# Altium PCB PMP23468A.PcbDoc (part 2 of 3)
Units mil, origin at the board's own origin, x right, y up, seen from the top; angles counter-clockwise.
Board outline 5250 x 3500 mil, 6 copper layers (Top Layer, Signal Layer 1, Signal Layer 2, Signal Layer 3, Signal Layer 4, Bottom Layer), stack 61.8 mil thick; 157 components, 73 nets, 403 pads, 842 vias.

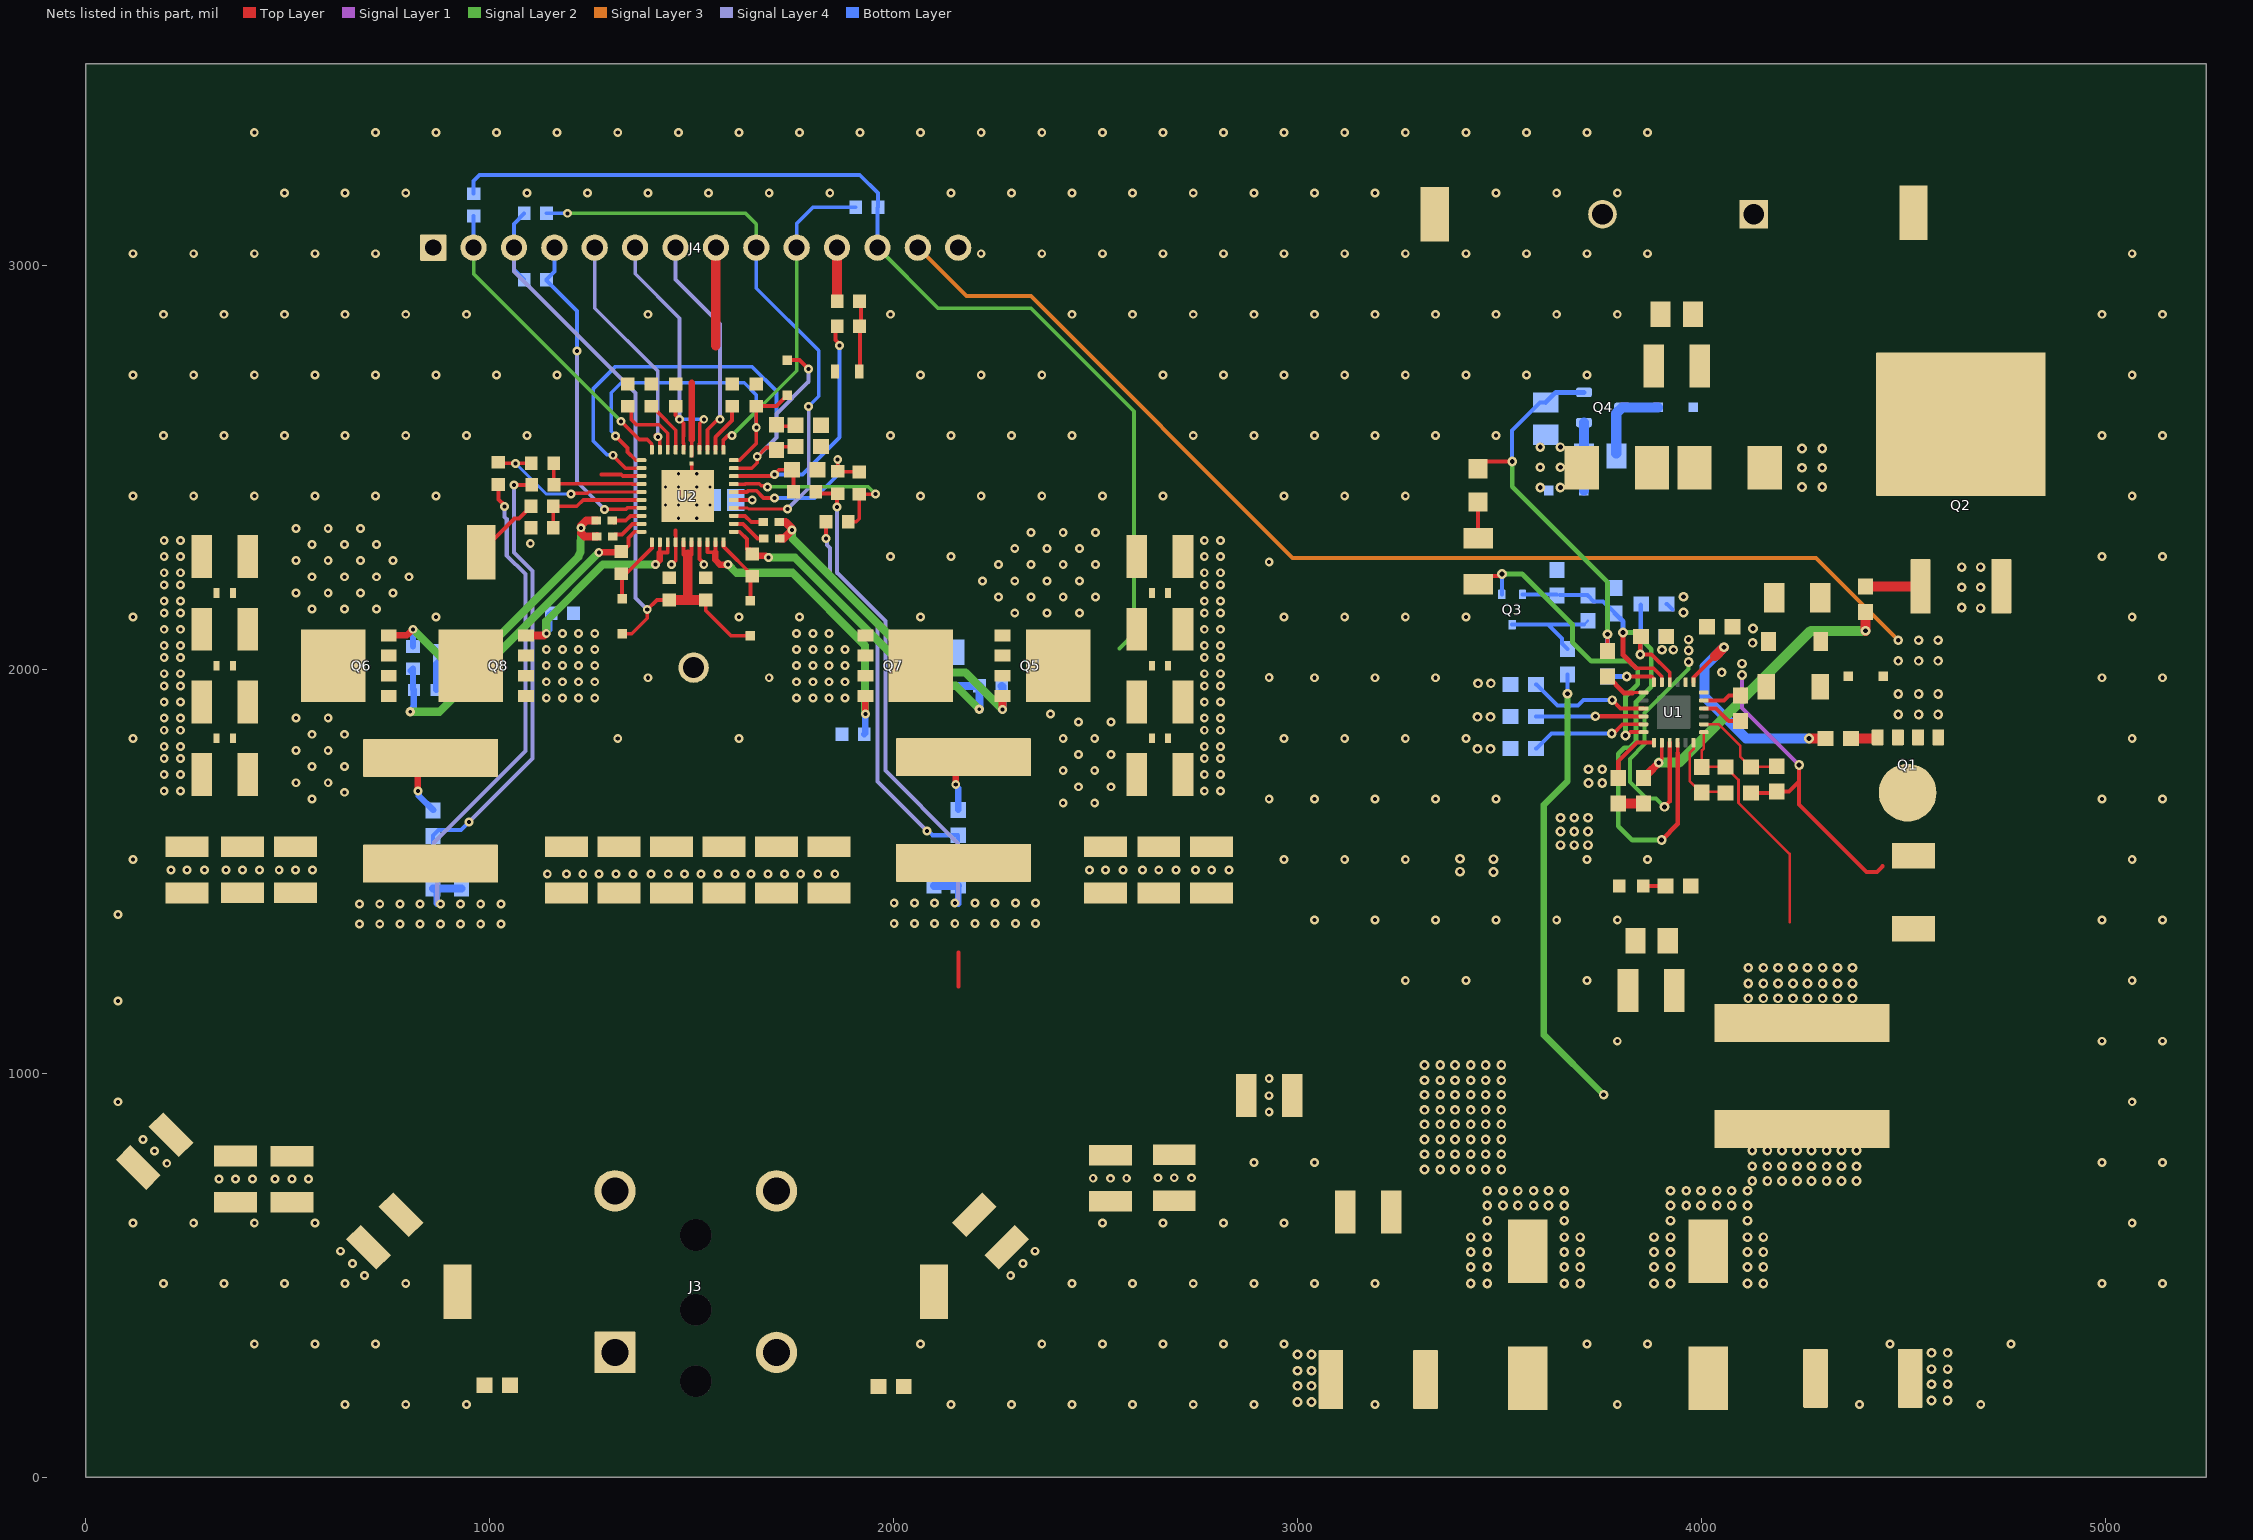
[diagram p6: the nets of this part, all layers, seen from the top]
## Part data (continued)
R9: library part CMP-0022456-4, "RES, 4.75 k, 1%, 0.1 W, AEC-Q200 Grade 0, 0603", Manufacturer=Vishay-Dale, Power_W=100mW, Supplier Part Number 1=541-4.75KHCT-ND, TempCo="100 ppm/C", Tolerance_%=1%, Value2=0.1W, Value_Code=4k75, ValueDisplayed=4.75k
R10 R16: library part CMP-0018576-3, "RES, 10 k, 5%, 0.25 W, AEC-Q200 Grade 0, 1206", Manufacturer=Vishay-Dale, Power_W=250mW, Supplier Part Number 1=541-10KECT-ND, TempCo="200 ppm/C", Tolerance_%=5%, Value2=0.25W, Value_Code=10k0, ValueDisplayed=10k
R11: library part CMP-0022134-4, "RES, 1.82 k, 1%, 0.1 W, AEC-Q200 Grade 0, 0603", Manufacturer=Vishay-Dale, PartNumber=CRCW06031K82FKEA, Power_W=100mW, Supplier Part Number 1=541-1.82KHCT-ND, TempCo="100 ppm/C", Tolerance_%=1%, Value2=0.1W, Value_Code=1k82, ValueDisplayed=1.82k
R12: library part CMP-0022479-4, "RES, 50, 1%, 0.1 W, AEC-Q200 Grade 0, 0603", Manufacturer=Vishay-Dale, Power_W=100mW, Supplier Part Number 1=89M6778, TempCo="100 ppm/C", Tolerance_%=1%, Value2=0.1W, Value_Code=50R0, ValueDisplayed=50
R14: library part CMP-0022132-4, "RES, 1.74 k, 1%, 0.1 W, AEC-Q200 Grade 0, 0603", Manufacturer=Vishay-Dale, Power_W=100mW, Supplier Part Number 1=541-1.74KHCT-ND, TempCo="100 ppm/C", Tolerance_%=1%, Value2=0.1W, Value_Code=1k74, ValueDisplayed=1.74k
R15 R19 R33 R34: library part CMP-0023341-3, "RES, 10.0 k, 1%, 0.1 W, AEC-Q200 Grade 0, 0603", Manufacturer="Stackpole Electronics Inc", Power_W=100mW, Supplier Part Number 1=RMCF0603FT10K0CT-ND, TempCo="100 ppm/C", Tolerance_%=1%, Value2=0.1W, Value_Code=10k0, ValueDisplayed=10.0k
R17: library part CMP-0022112-4, "RES, 1.07 k, 1%, 0.1 W, AEC-Q200 Grade 0, 0603", Manufacturer=Vishay-Dale, PartNumber=CRCW06031K07FKEA, Power_W=100mW, Supplier Part Number 1=541-1.07KHCT-ND, TempCo="100 ppm/C", Tolerance_%=1%, Value2=0.1W, Value_Code=1k07, ValueDisplayed=1.07k
R18: library part CMP-0025700-4, "RES, 100, 5%, 0.1 W, AEC-Q200 Grade 0, 0603", Manufacturer=Vishay-Dale, Power_W=100mW, Supplier Part Number 1=541-100GCT-ND, TempCo="200 ppm/C", Tolerance_%=5%, Value2=0.1W, Value_Code=100R, ValueDisplayed=100
R20: library part CMP-0022377-4, "RES, 3.48 k, 1%, 0.1 W, AEC-Q200 Grade 0, 0603", Manufacturer=Vishay-Dale, PartNumber=CRCW06033K48FKEA, Power_W=100mW, Supplier Part Number 1=541-3.48KHCT-ND, TempCo="100 ppm/C", Tolerance_%=1%, Value2=0.1W, Value_Code=3k48, ValueDisplayed=3.48k
R21: library part CMP-0022067-4, "RES, 15.4 k, 1%, 0.1 W, AEC-Q200 Grade 0, 0603", Manufacturer=Vishay-Dale, PartNumber=CRCW060315K4FKEA, Power_W=100mW, Supplier Part Number 1=541-15.4KHCT-ND, TempCo="100 ppm/C", Tolerance_%=1%, Value2=0.1W, Value_Code=15k4, ValueDisplayed=15.4k
R22: library part CMP-0022900-4, "RES, 1.00, 1%, 0.1 W, 0603", Manufacturer=Yageo, Power_W=100mW, Supplier Part Number 1=311-1.00HRCT-ND, TempCo="200 ppm/C", Tolerance_%=1%, Value2=0.1W, Value_Code=1R00, ValueDisplayed=1.00
R23 R24 R26 R27: library part CMP-0026992-3, "RES, 0, 5%, 0.1 W, AEC-Q200 Grade 0, 0402", Manufacturer=Panasonic, Power_W=100mW, Supplier Part Number 1=P0.0JCT-ND, TempCo="600 ppm/C", Tolerance_%=5%, Value2=0.1W, Value_Code=0000, ValueDisplayed=0
R29 R30: library part CMP-0022000-4, "RES, 10.5 k, 1%, 0.1 W, AEC-Q200 Grade 0, 0603", Manufacturer=Vishay-Dale, Power_W=100mW, Supplier Part Number 1=541-10.5KHCT-ND, TempCo="100 ppm/C", Tolerance_%=1%, Value2=0.1W, Value_Code=10k5, ValueDisplayed=10.5k
R31 R32: library part CMP-0020693-3, "RES, 2.2, 5%, 0.125 W, AEC-Q200 Grade 0, 0805", Manufacturer=Panasonic, Power_W=125mW, Supplier Part Number 1=P2.2ACT-ND, TempCo="600 ppm/C", Tolerance_%=5%, Value2=0.125W, Value_Code=2R20, ValueDisplayed=2.2
R37 R40 R51: library part CMP-0025697-4, "RES, 0, 5%, 0.1 W, AEC-Q200 Grade 0, 0603", Manufacturer=Vishay-Dale, Power_W=100mW, Supplier Part Number 1=541-0.0GCT-ND, TempCo="200 ppm/C", Tolerance_%=5%, Value2=0.1W, Value_Code=0000, ValueDisplayed=0
R38 R39: library part CMP-0021991-4, "RES, 100, 1%, 0.1 W, AEC-Q200 Grade 0, 0603", Manufacturer=Vishay-Dale, Power_W=100mW, Supplier Part Number 1=541-100HCT-ND, TempCo="100 ppm/C", Tolerance_%=1%, Value2=0.1W, Value_Code=100R, ValueDisplayed=100
R41: library part CMP-0022441-4, "RES, 487 k, 1%, 0.1 W, AEC-Q200 Grade 0, 0603", Manufacturer=Vishay-Dale, PartNumber=CRCW0603487KFKEA, Power_W=100mW, Supplier Part Number 1=541-487KHCT-ND, TempCo="100 ppm/C", Tolerance_%=1%, Value2=0.1W, Value_Code=487k
R42: library part CMP-0022111-4, "RES, 1.05 k, 1%, 0.1 W, AEC-Q200 Grade 0, 0603", Manufacturer=Vishay-Dale, Power_W=100mW, Supplier Part Number 1=541-1.05KHCT-ND, TempCo="100 ppm/C", Tolerance_%=1%, Value2=0.1W, Value_Code=1k05, ValueDisplayed=1.05k
R43: library part CMP-0022452-4, "RES, 4.32 k, 1%, 0.1 W, AEC-Q200 Grade 0, 0603", Manufacturer=Vishay-Dale, Power_W=100mW, Supplier Part Number 1=541-4.32KHCT-ND, TempCo="100 ppm/C", Tolerance_%=1%, Value2=0.1W, Value_Code=4k32, ValueDisplayed=4.32k
R48: library part CMP-0022494-4, "RES, 54.9 k, 1%, 0.1 W, AEC-Q200 Grade 0, 0603", Manufacturer=Vishay-Dale, Power_W=100mW, Supplier Part Number 1=541-54.9KHCT-ND, TempCo="100 ppm/C", Tolerance_%=1%, Value2=0.1W, Value_Code=54k9, ValueDisplayed=54.9k
R49: library part CMP-0022018-4, "RES, 11.5 k, 1%, 0.1 W, AEC-Q200 Grade 0, 0603", Manufacturer=Vishay-Dale, Power_W=100mW, Supplier Part Number 1=541-11.5KHCT-ND, TempCo="100 ppm/C", Tolerance_%=1%, Value2=0.1W, Value_Code=11k5, ValueDisplayed=11.5k
R50: library part CMP-0025686-1, "RES, 10.0 k, 0.1%, 0.1 W, AEC-Q200 Grade 1, 0603", Manufacturer=Vishay-Dale, PartNumber=TNPW060310K0BEEA, Power_W=100mW, Supplier Part Number 1=TNP10.0KAACT-ND, TempCo="25 ppm/C", Tolerance_%=0.1%, Value2=0.1W, Value_Code=10k0, ValueDisplayed=10.0k
SH-J1: library part CMP-0078738-1, "Single Operation 2.54mm Pitch Open Top Jumper Socket", Manufacturer=Harwin, Supplier Part Number 1=952-2881-ND
TP1 TP2 TP3 TP4 TP5: library part CMP-0055152-2, "Test Point, Miniature, SMT", Manufacturer="Keystone Electronics", Supplier Part Number 1=36-5015TR-ND
U1: library part CMP-0021701-1, "Ideal Diode Surge Stopper with Circuit breaker, overvoltage protection and fault output", Manufacturer="Texas Instruments", Max Supply Voltage=65V, Min Supply Voltage=3V, Nominal Supply Current=650-700uA, Operating Temperature Range="-40°C to +150°C"
U2: library part CMP-0094639-1, "Automotive 3.5-V to 65-V Dual Synchronous Buck Controller With Low IQ", Manufacturer="Texas Instruments", Max Supply Voltage=65V, Min Supply Voltage=3.5V, Nominal Supply Current=15-25uA, Operating Temperature Range="-40°C to +150°C", Output Voltage=0.6-55V, Switching Frequency=0.1-2.2MHz

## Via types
v1: diameter 22, hole 10, Top Layer to Bottom Layer, tented both sides, 567 vias
v2: diameter 24, hole 12, Top Layer to Bottom Layer, tented both sides, 172 vias
v3: diameter 24, hole 12, Top Layer to Bottom Layer, 84 vias
v4: diameter 19.68, hole 7.87, Top Layer to Bottom Layer, 12 vias
v5: diameter 19.68, hole 7.87, Top Layer to Bottom Layer, tented both sides, 5 vias
v6: diameter 24, hole 8, Top Layer to Bottom Layer, tented both sides, 2 vias

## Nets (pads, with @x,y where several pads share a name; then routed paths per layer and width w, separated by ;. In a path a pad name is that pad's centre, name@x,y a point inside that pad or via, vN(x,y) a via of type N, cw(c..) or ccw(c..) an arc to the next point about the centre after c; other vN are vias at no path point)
A: C1.1 D5.2 J4.13 Q1.1 Q1.2 Q1.3 Q2.3 U1.2 U1.15 | length 3462.7
  Top Layer w10: v3(3909.01,1660.24) 3921.86,1673.1 U1.15@3921.86,1819.51
  Signal Layer 2 w10: v3(3909.01,1660.24) 3887.93,1681.32 3864.71,1681.32 3823.71,1722.32 3823.71,1779.32 3859.91,1815.52 3859.91,1892.52 3968.61,2001.22 v3(3968.61,2018.87)
  Signal Layer 3 w10: J4.13@2060,3045 2180,2925 2340,2925 2988.01,2276.99 4283.64,2276.99 v3(4487.81,2072.82)
  other v3: 4487.81,1888.82 4538.11,1888.82 4586.41,1888.82 4487.81,1939.82 4538.11,1939.82 4586.41,1939.82 4487.81,2021.82 4538.11,2021.82 4586.41,2021.82 3968.61,2047.22 4538.11,2072.82 4586.41,2072.82 3968.61,2074.32 4691.71,2152.32 4644.91,2153.92 4644.91,2203.92 4691.71,2203.92 4644.91,2253.92 4691.71,2253.92
AGND: C18.1 C66.1 C67.2 C68.2 C69.2 C70.2 J4.8 NT1.1 R48.1 R50.1 R51.2 U2.3 U2.35 | length 523.6
  Top Layer w9: NT1.1@1499.84,2530 U2.35@1499.84,2544.17 1499.84,2569.84
  Top Layer w9.5: 1276.38,2483.62 1324.79,2483.62 1329.2,2479.21 U2.3@1375.83,2479.21
  Top Layer w16: 1499.84,2569.84 1500,2570 1500,2710
  Top Layer w24: 1560,2802.78 J4.8@1560,3045
COMP: C69.1 D11.2 R49.2 U2.2 U2.29 | length 1486.8
  Top Layer w9: v1@1310,2530 1309.07,2530.93 v1(1305,2530.93) 1305,2530 1336.1,2498.9 U2.2@1375.83,2498.9 ; U2.29@1604.17,2498.9 1648.9,2498.9 1662.44,2512.44 v1(1662.44,2527.44) 1685,2550 1707.44,2550 1710,2547.44 1714.75,2552.19 C69.1@1761.33,2552.19
  Top Layer w10: D11.2@1737.15,2766.33 1767.49,2766.33 v1(1789.59,2744.23)
  Signal Layer 4 w10: v1(1662.44,2527.44) 1710,2575 1710,2633.35 1789.59,2712.94 v1(1789.59,2744.23)
  Bottom Layer w9: v1(1305,2530.93) 1303.4,2532.53 1289.95,2532.53 1256.7,2565.78 1256.7,2696.2 1310.16,2749.67 1611.14,2749.99 ; 1611.14,2749.69 1650.32,2749.69 1710,2690 1710,2575 v1(1662.44,2527.44)
DEMB: J4.7 U2.33 | length 550
  Top Layer w9: U2.33@1539.21,2544.17 1539.21,2594.21 1560,2615
  Signal Layer 4 w9: J4.7@1460,3045 1460,2965.98 1570,2855.98 v1(1570,2620)
EN1: J4.10 R47.1 U2.31 | length 804.4
  Top Layer w9: U2.31@1578.58,2544.17 1578.58,2568.58 1590,2580 v1(1600,2580)
  Signal Layer 2 w9: v1(1600,2580) 1760,2740 J4.10@1760,3045
  Bottom Layer w9: J4.10@1760,3045 1760,3104.76 1800.24,3145 R47.1@1906.18,3145
EN2: J4.2 R46.1 U2.40 | length 773.5
  Top Layer w9: v1(1325,2615) 1370,2570 1390,2570 1401.42,2558.58 U2.40@1401.42,2544.17
  Signal Layer 2 w9: J4.2@960,3045 960,2980 v1(1325,2615)
  Bottom Layer w10: J4.2@960,3045 R46.1@960,3123.11
FB1: R41.1 R43.1 R50.2 U2.28 | length 688.3
  Top Layer w9.5: U2.28@1604.17,2479.21 1700.79,2479.21 v1(1705,2483.43) 1716.57,2495 R50.2@1748.5,2495 1752.44,2495 R41.1@1752.44,2440
  Top Layer w10: R43.1@1856.57,2850.31 1856.57,2815.87 1866.41,2806.03 v1(1866.41,2802.78)
  Bottom Layer w10: v1(1705,2483.43) 1774.36,2483.43 1866.41,2575.47 v1(1866.41,2802.78)
FLT/: Q3.1 R16.1 U1.12 | length 804.3
  Top Layer w10: R16.1@3447.56,2211.27 3468.15,2231.86 3498.86,2231.86 3503.86,2236.86 v3(3506.57,2236.86) ; v3(3812.32,1836.8) 3816.11,1836.8 3824.41,1845.11 U1.12@3856.9,1845.11
  Signal Layer 2 w12: v3(3506.57,2236.86) 3556.16,2236.86 3680.71,2112.32 3680.71,2068.32 3727.71,2021.32 3820.81,2021.32 3842.71,1999.42 3842.71,1964.32 3812.32,1933.93 v3(3812.32,1836.8)
  Bottom Layer w6: Q3.1@3506.12,2186.17 Q3.1@3506.34,2186.4 ; v3@3506.34,2236.64 v3(3506.57,2236.86)
  Bottom Layer w10: Q3.1@3506.34,2186.4 v3@3506.34,2236.64 ; v3(3506.57,2236.86) v3@3506.76,2237.06
NetC2_2: C2.2 R6.2
NetC3_2: C3.2 R7.2
NetC6_1: C6.1 C7.1 C12.2 C13.2 L1.1 R1.2 R2.1 U1.19 | length 597.6
  Top Layer w6.5: U1.19@4006.51,1845.11 4006.51,1805.12 4001.21,1799.82 C12.2@4001.21,1759.31 C13.2@4060.21,1759.32 4092.21,1727.32 4092.21,1670.12 4218.71,1543.62 4218.71,1374.32
  other v2: 4116.23,1186.13 4153.63,1186.13 4189.7,1186.13 4227.11,1186.13 4263.03,1186.13 4300.44,1186.13 4337.17,1186.13 4374.58,1186.13 4116.23,1222.75 4153.63,1222.75 4189.7,1222.75 4227.11,1222.75 4263.03,1222.75 4300.44,1222.75 4337.17,1222.75 4374.58,1222.75 4116.23,1261.8 4153.63,1261.8 4189.7,1261.8 4227.11,1261.8 4263.03,1261.8 4300.44,1261.8 4337.17,1261.8 4374.58,1261.8
NetC9_1: C9.1 C11.1 D5.1 D7.1 R10.2 U1.22 | length 103.2
  Top Layer w10: U1.22@4006.51,1904.16 4036.59,1904.16 4067.93,1872.82 C9.1@4096.71,1872.82
NetC9_2: C9.2 U1.23 | length 95.2
  Top Layer w9.6: U1.23@4006.51,1923.85 4056.27,1923.85 4068.24,1935.81 4082.71,1935.81 C9.2@4096.71,1935.81
NetC12_1: C12.1 R11.2 U1.18 | length 202
  Top Layer w6.5: U1.18@3980.92,1819.51 3980.92,1803.43 3971.26,1793.76 3971.26,1724.07 3999,1696.32 C12.1@4001.21,1696.32 4002.71,1697.82 4056.71,1697.82 R11.2@4060.21,1694.32
NetC13_1: C13.1 R12.2 U1.20 | length 240.4
  Top Layer w6.5: U1.20@4006.51,1864.79 4043.4,1864.79 4096.71,1811.48 4096.71,1784.32 4121.71,1759.32 C13.1@4123.2,1759.32 4185.21,1759.32 R12.2@4186.71,1760.81
NetC14_1: C14.1 R13.2 R14.1 U1.4 | length 275.9
  Top Layer w9.6: v3(3848.66,2037.53) 3877.02,2037.53 3921.86,1992.68 U1.4@3921.86,1969.12
  Top Layer w12: v3(3848.66,2037.53) 3848.66,2072.76 C14.1@3850.21,2074.32
  Bottom Layer w12: v3(3848.66,2037.53) 3848.66,2080.76 R14.1@3850.21,2082.32 R13.2@3850.21,2160
NetC15_1: C15.1 R18.2 | length 62.7
  Top Layer w25: C15.1@3794.32,1668.82 R18.2@3856.98,1668.82
NetC16_1: C16.1 U1.9 | length 301.7
  Top Layer w9.6: v3(3779.43,1924.47) 3799.74,1904.16 U1.9@3856.9,1904.16
  Bottom Layer w10: C16.1@3590.75,1963.22 3591.73,1963.22 3643.81,1911.14 3694.78,1911.14 3708.11,1924.47 v3(3779.43,1924.47)
NetC19_1: C19.1 R22.1 U2.6 | length 275.9
  Top Layer w9: C19.1@1157.56,2351.98 1157.56,2399.84 R22.1@1159.86,2402.14 ; R22.1@1157.56,2404.43 1215.79,2404.43 1231.51,2420.16 U2.6@1375.83,2420.16
NetC36_1: C36.1 C44.1 L2.1 Q5.1 Q5.2 Q5.3 Q7.5 R25.2 R29.2 U2.21 | length 1067.4
  Top Layer w9.5: U2.21@1604.17,2341.42 1618.58,2341.42 1636.87,2323.13 1636.87,2298.17 C36.1@1645.22,2289.83 ; C36.1@1650.36,2295.37 C36.1@1660.04,2285.69
  Top Layer w10: L2.1@2153.92,1777.94 L2.1@2154.16,1778.19
  Top Layer w16: C36.1@1645.22,2294.83 1645.22,2290.81 1653.95,2282.08 1683.97,2282.08 1688.17,2277.87 v1(1689.8,2277.87) ; v1(2153.92,1715.59) L2.1@2153.92,1777.94
  Signal Layer 2 w20: v1@1690.72,2277.49 1755.39,2277.49 2072.7,1960.19 2153.86,1960.19 v6(2212.23,1901.82) v6@2212.23,1902.9
  Bottom Layer w6: C44.1@2126.5,1960.19 C44.1@2126.92,1959.76 ; R25.2@2212.23,1959.28 R25.2@2212.72,1959.76
  Bottom Layer w10: R29.2@2159.75,1653.24 R29.2@2160,1652.99
  Bottom Layer w16: R29.2@2159.75,1653.24 v1@2159.75,1706.3
  Bottom Layer w20: 2143.06,1959.76 R25.2@2212.72,1959.76 ; v6(2212.23,1901.82) R25.2@2212.23,1959.28
NetC36_2: C36.2 D9.1 U2.20 | length 178
  Top Layer w9.5: U2.20@1578.58,2315.83 1578.58,2305.13 C36.2@1651.26,2232.45 ; D9.1@1645.22,2170.48 1645.62,2170.89 1645.62,2230.62 1645.22,2231.03 C36.2@1645.22,2234.71
NetC37_1: C37.1 C45.1 L3.1 Q6.1 Q6.2 Q6.3 Q8.5 R28.1 R30.1 U2.10 | length 1004.7
  Top Layer w9.5: C37.1@1331.69,2296.14 1332.27,2296.14 1343.26,2307.14 1343.26,2326.04 1358.64,2341.42 U2.10@1375.83,2341.42
  Top Layer w16: L3.1@820.22,1764.3 822.11,1762.41 v1(822.11,1699.58) ; v1(1270,2290) 1271.15,2291.15 1317.96,2291.15 C37.1@1322.95,2296.14
  Signal Layer 2 w20: v6(803.01,1895.83) 875.83,1895.83 v1(1270,2290)
  Bottom Layer w10: v1(822.11,1699.58) v1@824.4,1697.29 ; R30.1@860,1651.5 R30.1@860,1652.48
  Bottom Layer w16: v6(803.01,1895.83) 803.01,1899.62 812,1908.61 C45.1@812,1950 ; R28.1@804.81,1997.25 R28.1@810,2002.44 C45.1@810,1952 ; v1@824.4,1697.29 824.4,1688.08 R30.1@860,1652.48
NetC37_2: C37.2 D10.1 U2.11 | length 179.8
  Top Layer w9.5: D10.1@1326.25,2176.36 1327.71,2177.82 1327.71,2237.04 C37.2@1331.69,2241.02 ; C37.2@1327.71,2241.65 1341.65,2241.65 1401.42,2301.42 U2.11@1401.42,2315.83
NetC44_2: C44.2 R31.2 | length 83
  Bottom Layer w6: R31.2@2070,2043.01 R31.2@2070.5,2042.51
  Bottom Layer w20: C44.2@2070.5,1960.19 R31.2@2070.5,2042.51
NetC45_2: C45.2 R32.2 | length 88.9
  Bottom Layer w16: C45.2@868,1950 868,2014.81 R32.2@885,2031.81
NetC52_1: C52.1 R29.1 R33.2 R38.2 | length 1073.4
  Top Layer w10: R38.2@1832.44,2366.1 1832.8,2365.74 v1(1832.8,2324.88)
  Signal Layer 4 w10: v1(1832.8,2324.88) 1835.1,2322.59 1835.1,2308.45 1842.13,2301.42 1842.13,2232.6 1960,2114.72 1960,1723.18 v1(2082.32,1600.86)
  Bottom Layer w10: v1(2082.32,1600.86) 2085.57,1600.86 2096.42,1590 R29.1@2160,1590 C52.1@2160,1527.88 R33.2@2099.64,1527.88
NetC53_2: C53.2 R30.2 R34.1 R39.2 | length 1198
  Top Layer w10: v1(1060,2457.56) R39.2@1104.11,2457.56
  Signal Layer 4 w10: v1(948.7,1623.19) 1105.93,1780.42 1105.93,2244.07 1060,2290 v1(1060,2457.56)
  Bottom Layer w10: R30.2@860,1583.22 C53.2@860,1521.5 R34.1@930,1521.5 ; R30.2@860,1588.5 860,1589.49 873.7,1603.19 928.7,1603.19 v1(948.7,1623.19)
NetC54_1: C54.1 R37.1 U2.26 | length 412.2
  Top Layer w9: U2.26@1604.17,2439.84 1636.79,2439.84 1640.32,2443.37 1659.68,2443.37 1677.95,2425.1 v1(1705,2425.1) ; v1(1861.65,2520.59) R37.1@1861.65,2491 1863.01,2489.65 C54.1@1915.04,2489.65
  Bottom Layer w9: v1(1705,2425.1) 1705.1,2425 1804.51,2425 1861.65,2482.14 v1(1861.65,2520.59)
NetC54_2: C54.2 R38.1 U2.27 | length 496.9
  Top Layer w9: U2.27@1604.17,2459.53 1632.61,2459.53 1633.33,2460.25 1667.15,2460.25 1672.28,2455.13 1685.69,2455.13 v1(1688.17,2452.64) ; R38.1@1887.56,2366.1 1907.24,2366.1 1915.04,2373.9 C54.2@1915.04,2434.53 1944.7,2434.53 v1(1955.25,2434.91) v1@1951.73,2434.91
  Signal Layer 2 w9: v1(1688.17,2452.64) 1937.52,2452.64 v1(1955.25,2434.91)
NetC55_1: C55.1 R40.1 U2.5 | length 428.2
  Top Layer w8: R40.1@1021.61,2513.7 1024.41,2510.9 v1(1063.76,2510.9) C55.1@1103.11,2510.9 ; v1(1201.03,2435) 1202.66,2436.63 1242.14,2436.63 1245.36,2439.84 U2.5@1375.83,2439.84
  Bottom Layer w8: v1(1063.76,2510.9) 1139.66,2435 v1(1201.03,2435)
NetC55_2: C55.2 R39.1 U2.4 | length 266.7
  Top Layer w9: C55.2@1157.75,2511.37 C55.2@1158.23,2510.9 1158.23,2463.44 1161.67,2460 1353.06,2460 ; 1353.53,2459.53 U2.4@1375.83,2459.53
NetC66_2: C66.2 R42.1 R43.2 | length 170.5
  Top Layer w10: C66.2@1916.5,2738.57 R43.2@1916.5,2847.28 ; R43.2@1919.56,2850.31 R42.1@1919.56,2912.07
NetC68_1: C68.1 U2.32 | length 125.3
  Top Layer w9: U2.32@1558.9,2544.17 1558.9,2575.84 1600,2616.94 C68.1@1600,2652.44
NetC70_1: C70.1 R49.1 | length 52.5
  Top Layer w9: R49.1@1710,2602.56 1758.58,2602.56 C70.1@1761.33,2605.32
NetD1_2: D1.2 D3.1
NetD2_1: D2.1 Q4.3 R8.1 | length 209.2
  Bottom Layer w25: R8.1@3789.46,2535.07 3789.46,2634.83 Q4.3@3803.95,2649.32 D2.1@3892.91,2649.32
NetD4_1: D4.1 R2.2 | length 54.7
  Top Layer w10: D4.1@3856.21,1464.36 R2.2@3910.92,1464.36
NetD6_1: D6.1 Q4.1 R8.2 | length 162.6
  Bottom Layer w10: R8.2@3709.11,2528.4 R8.2@3709.82,2529.1
  Bottom Layer w25: D6.1@3709.11,2443.59 R8.2@3709.11,2528.4 ; R8.2@3709.46,2535.07 Q4.1@3709.46,2611.92
NetD8_2: D8.2 R16.2 | length 89.3
  Top Layer w10: R16.2@3447.56,2325.45 D8.2@3447.56,2414.74
NetQ1_4: Q1.4 R3.1 | length 66
  Top Layer w25: R3.1@4370.72,1829.44 Q1.4@4436.71,1829.44
NetQ1_5-6: Q1.5-6 R1.1 R11.1 R12.1 U1.24 | length 784.6
  Top Layer w10: R11.1@4123.2,1694.32 R12.1@4183.2,1694.32 ; R12.1@4186.71,1697.82 4216.85,1697.82 4239.53,1720.5 ; v3(4242.21,1763.77) 4242.21,1720.5 4242.21,1665.58 4408.75,1499.04 4435.18,1499.04 4448.71,1512.56 4448.71,1514.17
  Signal Layer 1 w10: v3(4100.6,1986.64) 4100.6,1905.38 v3(4242.21,1763.77)
  other v3: 4050.71,1993.32 4100.6,2014.95
NetQ2_1: Q2.1 R5.1 | length 136.1
  Top Layer w25: R5.1@4406.71,2206.26 Q2.1@4542.81,2206.25
NetQ3_3: Q3.3 R4.2 R9.1 | length 271.9
  Bottom Layer w6: R9.1@3709.62,2111.37 R9.1@3719.28,2121.02
  Bottom Layer w10: Q3.3@3531.71,2111.37 3620.57,2111.37 ; R4.2@3668.28,2050.82 3654.58,2064.52 3654.58,2077.36 3620.57,2111.37 ; R9.1@3709.62,2111.37 3620.57,2111.37
NetQ5_4: Q5.4 R23.1 R25.1 R26.1 | length 892.5
  Top Layer w10: Q5.4@2269.96,1935 Q5.4@2269.96,1935
  Top Layer w20: R26.1@1716.79,2365.74 1732.54,2365.74 1748.39,2349.89 v1(1748.39,2345.9) 1748.39,2345.36 1728.44,2325.41 1718.28,2325.41 R23.1@1718.12,2325.25 ; v1@2270,1900.98 v1(2270.08,1901.06) 2270.02,1901.12 Q5.4@2270.02,1934.94
  Signal Layer 2 w20: v1(1748.39,2345.9) 1748.39,2326.33 2081.54,1993.18 2177.97,1993.18 v1(2270.08,1901.06)
  Bottom Layer w20: R25.1@2267.83,1959.76 2269.7,1957.9 2269.7,1901.45 v1(2270.08,1901.06)
NetQ6_4: Q6.4 R24.2 R27.2 R28.2 | length 813.1
  Top Layer w16: Q6.4@750.04,2085 795,2085 v1(810,2100)
  Top Layer w20: 1225.53,2338.19 1226.69,2338.19 1234.73,2330.16 R24.2@1265.31,2330.16 R24.2@1265.16,2330.31 ; v1@1226.01,2351.69 1226.01,2356.31 1238.93,2369.23 1263.75,2369.23 R27.2@1263.9,2369.38
  Signal Layer 2 w20: v1(810,2100) 878.19,2031.81 971.81,2031.81 1219.32,2279.32 1225.17,2293.3 v1(1225.63,2351.31)
  Bottom Layer w16: R28.2@810,2057.56 v1(810,2100)
NetQ7_4: Q7.4 R35.1 U2.18 U2.19 | length 815.1
  Top Layer w9.5: U2.18@1539.21,2315.83 1539.21,2290.79 1558.11,2290.79 1558.9,2290 U2.19@1558.9,2315.83
  Top Layer w10: Q7.4@1929.96,1935 Q7.4@1929.96,1935
  Top Layer w16: 1558.11,2290.79 1558.11,2271.89 1570,2260 v1(1590,2260) ; v1(1930,1890) Q7.4@1929.96,1935
  Signal Layer 2 w20: v1(1590,2260) 1590.54,2260 1610.54,2240 1749.45,2240 1929.62,2059.83 1929.62,1890.38 v1(1930,1890)
  Bottom Layer w16: R35.1@1927.56,1840 1930,1842.44 v1(1930,1890)
NetQ8_4: Q8.4 R36.2 U2.12 U2.13 | length 570.7
  Top Layer w9.5: U2.12@1421.1,2315.83 1421.1,2290 1440,2290 1440.79,2290.79 U2.13@1440.79,2315.83
  Top Layer w16: v1(1410,2260) 1421.1,2271.1 1421.1,2290
  Top Layer w20: Q8.4@1090.04,2085 1134.49,2085 1139.49,2090 v1(1140,2090)
  Signal Layer 2 w20: v1(1140,2090) 1140,2120 1280,2260 v1(1410,2260)
  Bottom Layer w16: v1(1140,2090) 1140.03,2091.62 1147.67,2099.27 1147.67,2135.23 R36.2@1152.44,2140
NetR3_2: R3.2 U1.1 | length 602
  Top Layer w9.6: U1.1@3980.92,1969.12 3980.92,1980.23 4034.22,2033.53
  Top Layer w25: 4034.22,2033.53 v3(4056.02,2055.33) ; v3(4266.6,1829.44) R3.2@4307.72,1829.44
  Bottom Layer w25: v3(4056.02,2055.33) 4008.31,2007.62 4008.31,1932.44 4111.31,1829.44 v3(4266.6,1829.44)
NetR5_2: R5.2 R18.1 U1.14 | length 790.8
  Top Layer w9.6: v3@3902.18,1777.02 U1.14@3902.18,1819.51
  Top Layer w20: R18.1@3856.98,1731.81 3856.98,1732.8 3865.68,1741.5 3866.66,1741.5 v3(3894.8,1769.63)
  Top Layer w25: v3(4406.71,2096.22) R5.2@4406.71,2143.26
  Signal Layer 2 w25: v3(3894.8,1769.63) 3944.74,1769.63 4271.33,2096.22 v3(4406.71,2096.22)
NetR15_2: R15.2 U1.6 | length 127.3
  Top Layer w9.6: v3@3813.31,1983.21 v3(3815.31,1983.21) 3876.78,1983.21 3882.49,1977.49 U1.6@3882.49,1969.12
  Bottom Layer w12: R15.2@3767.9,1983.21 v3(3815.31,1983.21)
NetR19_2: R19.2 U1.7 | length 106.2
  Top Layer w8: 3829.56,1942.62 3830.46,1943.53 U1.7@3856.9,1943.53
  Top Layer w12: R19.2@3767.9,1983.21 3808.49,1942.62 3829.56,1942.62
NetR20_2: R20.2 U1.10 | length 266.2
  Top Layer w9.6: 3828.7,1884.48 U1.10@3856.9,1884.48
  Top Layer w12: v3(3737.65,1884.48) 3828.7,1884.48
  Bottom Layer w10: R20.2@3590.75,1884.48 v3(3737.65,1884.48)
NetR21_1: R21.1 U1.11 | length 291.4
  Top Layer w9.6: v3(3778.28,1841.9) 3782.15,1841.9 3805.04,1864.79 U1.11@3856.9,1864.79
  Bottom Layer w10: R21.1@3590.75,1804.32 3591.73,1804.32 3629.53,1842.12 3778.06,1842.12 v3(3778.28,1841.9)
NetR22_2: R22.2 TP3.1 | length 171.4
  Top Layer w10: TP3.1@978.7,2290.81 1061.67,2373.78 1072.77,2373.78 1102.44,2403.45 R22.2@1102.44,2404.43
NetR23_2: R23.2 U2.22 | length 89.4
  Top Layer w9.8: U2.22@1604.17,2361.1 1627.15,2361.1 1663,2325.25 R23.2@1678.75,2325.25
NetR24_1: R24.1 U2.9 | length 84
  Top Layer w9.8: R24.1@1304.68,2330.16 1309.63,2335.1 1327.54,2335.1 1353.53,2361.09 U2.9@1375.83,2361.1
NetR26_2: R26.2 U2.23 | length 79.5
  Top Layer w9.8: U2.23@1604.17,2380.79 1632.46,2380.79 1647.5,2365.74 R26.2@1677.42,2365.74
NetR27_1: R27.1 U2.8 | length 83.6
  Top Layer w9.8: R27.1@1307.73,2364.93 R27.1@1303.27,2369.38 1336.83,2369.38 1348.23,2380.79 U2.8@1375.83,2380.79
NetR48_2: R48.2 U2.37 | length 114.1
  Top Layer w9: R48.2@1416.43,2637.1 1460.47,2593.06 U2.37@1460.47,2544.17
  Top Layer w10: R48.2@1400,2645.55 R48.2@1400,2648.5
NetR51_1: R51.1 U2.38 | length 182.3
  Top Layer w9: R51.1@1340,2652.44 1350,2640 1350,2620 1363.51,2606.49 1419.65,2606.49 1440.79,2585.35 U2.38@1440.79,2544.17
OV: C71.2 Q3.2 R9.2 R17.1 U1.5 U1.16 | length 1431.9
  Top Layer w9: U1.16@3941.55,1819.51 3941.55,1794.55 3941.71,1794.39
  Top Layer w9.6: 3839.2,2003.62 3881.76,2003.62 3902.18,1983.19 U1.5@3902.18,1969.12
  Top Layer w12: v3(3806.07,2091.86) 3806.12,2091.81 3806.12,2036.7 3839.2,2003.62 ; v3(3901.71,1578.09) 3941.71,1618.09 3941.71,1794.39
  Signal Layer 2 w12: v3(3806.07,2091.86) 3834.67,2091.86 3876.15,2050.37 3876.15,1957.56 3838.28,1919.69 3838.28,1821.92 3822.96,1806.6 3809.63,1806.6 3794.32,1791.29 3794.32,1612.71 3828.93,1578.09 v3(3901.71,1578.09)
  Bottom Layer w6: C71.2@3640.93,2186.17 C71.2@3642.97,2184.13
  Bottom Layer w10: Q3.2@3557.3,2186.17 C71.2@3640.93,2186.17 ; C71.2@3650.3,2184.6 3718.69,2184.6 R9.2@3719.28,2184.01 3719.28,2183.03 3732.98,2169.33 3756.11,2169.33 3771.43,2154 3772.42,2154 3786.12,2140.3 R17.1@3786.12,2139.32
  Bottom Layer w12: R17.1@3786.12,2139.32 3806.07,2119.37 v3(3806.07,2091.86)
PG1: J4.9 R45.1 U2.24 | length 1466.6
  Top Layer w7: U2.24@1604.17,2400.47 1604.17,2400 1638.36,2400 1640.73,2397.63 v1(1737.15,2397.63)
  Signal Layer 2 w9: v1(1192.97,3130) 1633.29,3130 1660,3103.29 J4.9@1660,3045
  Signal Layer 4 w9: v1(1737.15,2397.63) 1789.59,2450.06 v1(1789.59,2652.02)
  Bottom Layer w9: R45.1@1140.53,3130 v1(1192.97,3130) ; J4.9@1660,3045 1660,2944.52 1814.45,2790.07 1814.45,2676.88 v1(1789.59,2652.02)
PG2: J4.4 R44.1 U2.7 | length 808.9
  Top Layer w9: v1(1284.53,2396.78) 1336.49,2396.78 1340.18,2400.47 U2.7@1375.83,2400.47
  Signal Layer 4 w9: v1(1216.17,2788.59) 1216.17,2465.15 v1(1284.53,2396.78)
  Bottom Layer w10: J4.4@1160,3045 1160.21,3044.79 1160.21,2985.67 1140.53,2965.98 R44.1@1140.53,2965 1140.53,2964.02 1216.17,2888.37 v1(1216.17,2788.59)
PGND: C1.2 C4.1 C5.2 C6.2 C7.2 C8.2 C10.2 C11.2 C14.2 C15.2 C16.2 C17.1 C19.2 C20.2 C21.2 C22.2 C23.2 C24.2 C25.2 C26.2 C27.2 C28.2 C29.2 C30.2 C31.2 C32.2 C33.2 C34.2 C35.2 C38.2 C39.2 C40.2 C41.2 C42.2 C43.2 C46.2 C47.2 C48.2 C49.2 C50.2 C51.2 C56.2 C57.2 C58.2 C59.2 C60.2 C61.2 C62.2 C63.2 C64.2 C65.2 C71.1 D3.2 D4.2 D6.2 D7.2 J1.2 J2.1 J3.2 J4.1 J4.14 NT1.2 Q7.1 Q7.2 Q7.3 Q8.1 Q8.2 Q8.3 R6.1 R7.1 R14.2 R17.2 R20.1 R21.2 R31.1 R32.1 R35.2 R36.1 TP2.1 TP5.1 U1.13 U2.14 U2.17 U2.41 | length 358
  Top Layer w9: U2.41@1499.84,2449.84 NT1.2@1499.84,2510
  Top Layer w9.5: v1(1450,2260) 1460.47,2270.47 U2.14@1460.47,2315.83 1460,2345
  Top Layer w10: U2.17@1519.53,2315.83 1519.53,2273.72 1530,2263.25 v1(1530,2260) ; C15.2@3794.32,1731.81 3794.32,1772.53 3841.3,1819.51 U1.13@3882.49,1819.51
  other v1: 642,180 792,180 942,180 2142,180 2292,180 2442,180 2592,180 2742,180 2892,180 3192,180 3792,180 4392,180 4692,180 417,330 567,330 717,330 2067,330 2367,330 2517,330 2667,330 2817,330 2967,330 3717,330 3867,330 4467,330 4767,330 192,480 342,480 492,480 642,480 792,480 2442,480 2592,480 2742,480 2892,480 3042,480 3192,480 4992,480 5142,480 690,500 2290,500 660,530 2320,530 630,560 2350,560 117,630 267,630 417,630 567,630 2517,630 2667,630 2817,630 2967,630 5067,630 329.81,738.43 412.68,738.43 510.78,738.43 370.11,738.56 468.2,738.56 551.08,738.56 2494.32,740.66 2536.9,740.53 2577.2,740.66 2654.62,741.82 2694.92,741.95 2737.5,741.82 200.33,777.74 2892,780 3042,780 4992,780 5142,780 170.31,807.93 141.72,836.34 2930.13,904.75 80,930 5067,930 2930,945.05 2930.13,987.63 3792,1080 4992,1080 5142,1080 80,1180 3267,1230 3417,1230 3717,1230 5067,1230 3042,1380 3192,1380 3342,1380 3492,1380 3642,1380 3792,1380 4992,1380 5142,1380 80,1394.04 1142.49,1493.95 1190.07,1493.95 1230.37,1493.95 1270.65,1493.95 1312.97,1493.95 1355,1493.95 1399.49,1493.95 1442.07,1493.95 1482.37,1493.95 1522.65,1493.95 1564.97,1493.95 1607,1493.95 1646.86,1493.95 1689.43,1493.95 1729.74,1493.95 1770.01,1493.95 1812.33,1493.95 1854.37,1493.95 210.49,1504.03 250.79,1504.16 293.37,1504.03 347.2,1504.16 387.51,1504.29 430.08,1504.16 478.67,1504.16 518.97,1504.29 561.55,1504.16 2484.7,1504.03 2525,1504.16 2567.58,1504.03 2616.22,1504.03 2656.53,1504.16 2699.1,1504.03 2747.42,1504.03 2787.72,1504.16 2830.29,1504.03 117,1530 2967,1530 3117,1530 3267,1530 3717,1530 3867,1530 5067,1530 2930.13,1680 3042,1680 3192,1680 3342,1680 3492,1680 4992,1680 5142,1680 193.94,1700 233.94,1700 2769.34,1700 2809.34,1700 193.94,1740 233.94,1740 2769.34,1740 2809.34,1740 193.94,1780 233.94,1780 2769.34,1780 2809.34,1780 193.94,1810 233.94,1810 2769.34,1810 2809.34,1810 117,1830 1317,1830 1617,1830 2967,1830 3117,1830 3267,1830 3417,1830 5067,1830 193.94,1850 233.94,1850 2769.34,1850 2809.34,1850 193.94,1880 233.94,1880 2769.34,1880 2809.34,1880 193.94,1920 233.94,1920 2769.34,1920 2809.34,1920 1140,1930 1180,1930 1220,1930 1260,1930 1760,1930 1800,1930 1840,1930 1880,1930 193.94,1960 233.94,1960 2769.34,1960 2809.34,1960 1140,1970 1180,1970 1220,1970 1260,1970 1760,1970 1800,1970 1840,1970 1880,1970 1392,1980 1692,1980 3042,1980 3192,1980 3342,1980 4992,1980 5142,1980 2930.13,1980.7 193.94,1990 233.94,1990 2769.34,1990 2809.34,1990 1140,2010 1180,2010 1220,2010 1260,2010 1760,2010 1800,2010 1840,2010 1880,2010 193.94,2030 233.94,2030 2769.34,2030 2809.34,2030 1140,2050 1180,2050 1220,2050 1260,2050 1760,2050 1800,2050 1840,2050 1880,2050 193.94,2060 233.94,2060 2769.34,2060 2809.34,2060 1180,2090 1220,2090 1260,2090 1760,2090 1800,2090 1840,2090 193.94,2100 233.94,2100 2769.34,2100 2809.34,2100 117,2130 867,2130 1617,2130 1767,2130 2067,2130 2967,2130 3117,2130 3267,2130 3417,2130 5067,2130 193.94,2140 233.94,2140 2769.34,2140 2809.34,2140 193.94,2170 233.94,2170 2769.34,2170 2809.34,2170 193.94,2210 233.94,2210 2769.34,2210 2809.34,2210 193.94,2240 233.94,2240 2769.34,2240 2809.34,2240 2930.13,2266.29 193.94,2280 233.94,2280 1992,2280 2142,2280 2769.34,2280 2809.34,2280 4992,2280 5142,2280 1100.45,2312.87 193.94,2320 233.94,2320 2769.34,2320 2809.34,2320 117,2430 267,2430 417,2430 567,2430 717,2430 867,2430 2067,2430 2217,2430 2367,2430 2517,2430 2667,2430 2967,2430 3117,2430 3267,2430 5067,2430 192,2580 342,2580 492,2580 642,2580 792,2580 942,2580 1092,2580 1992,2580 2142,2580 2292,2580 2442,2580 2742,2580 2892,2580 3042,2580 3192,2580 3342,2580 3492,2580 4992,2580 5142,2580 117,2730 267,2730 417,2730 567,2730 717,2730 867,2730 1017,2730 1167,2730 2067,2730 2217,2730 2367,2730 2667,2730 2817,2730 2967,2730 3117,2730 3267,2730 3417,2730 3567,2730 3717,2730 5067,2730 192,2880 342,2880 492,2880 642,2880 792,2880 942,2880 1392,2880 1992,2880 2442,2880 2592,2880 2742,2880 2892,2880 3042,2880 3192,2880 3342,2880 3492,2880 3642,2880 3792,2880 4992,2880 5142,2880 117,3030 267,3030 417,3030 567,3030 717,3030 2217,3030 2367,3030 2517,3030 2667,3030 2817,3030 2967,3030 3117,3030 3267,3030 3417,3030 3567,3030 3717,3030 3867,3030 5067,3030 492,3180 642,3180 792,3180 1092,3180 1242,3180 1392,3180 1542,3180 1692,3180 1842,3180 2142,3180 2292,3180 2442,3180 2592,3180 2742,3180 2892,3180 3042,3180 3192,3180 3492,3180 3642,3180 3792,3180 417,3330 717,3330 867,3330 1017,3330 1167,3330 1317,3330 1467,3330 1617,3330 1767,3330 1917,3330 2067,3330 2217,3330 2367,3330 2517,3330 2667,3330 2817,3330 2967,3330 3117,3330 3267,3330 3417,3330 3567,3330 3717,3330 3867,3330
  other v2: 3000,186.58 3034.89,186.58 4570,190.47 4610,190.47 3000,226.54 3034.89,226.54 4570,230.43 4610,230.43 3000,264.19 3034.89,264.19 4570,268.08 4610,268.08 3000,304.49 3034.89,304.49 4570,308.38 4610,308.38
  other v3: 3485.57,1498.81 3402.59,1499.92 3485.57,1530.81 3402.59,1531.92 3651.28,1565.46 3685.28,1565.46 3719.28,1565.46 3651.28,1599.46 3685.28,1599.46 3719.28,1599.46 3651.28,1633.46 3685.28,1633.46 3719.28,1633.46 3720.73,1719.31 3754.73,1719.31 3720.73,1753.31 3754.73,1753.31 3445.82,1803.86 3477.82,1803.86 3445.82,1883.1 3477.82,1883.1 3446.93,1966.08 3478.93,1966.08 3902.68,2049.12 3930.92,2049.12 4127.1,2066.32 4128.03,2102.1 3601.04,2451.1 3651.04,2451.1 3601.04,2501.1 3651.04,2501.1 3601.04,2551.1 3651.04,2551.1
  other v4: 1467.36,2374.88 1512.64,2374.88 1434.88,2407.36 1467.36,2407.36 1512.64,2407.36 1545.12,2407.36 1434.88,2452.64 1467.36,2452.64 1512.64,2452.64 1545.12,2452.64 1467.36,2485.12 1512.64,2485.12
SS: C67.1 D11.1 U2.1 U2.30 | length 922.6
  Top Layer w9: v1(1311.63,2578.37) 1341.06,2548.94 1341.06,2538.94 1361.42,2518.58 U2.1@1375.83,2518.58 ; U2.30@1604.17,2518.58 1618.58,2518.58 1660,2560 v1(1660,2600) C67.1@1660,2652.44
  Top Layer w10: C67.1@1660,2652.44 1709.88,2652.44 D11.1@1737.15,2679.71
  Bottom Layer w9: v1(1311.63,2578.37) 1311.63,2579.36 1300.84,2590.15 1300.84,2685.84 1325.32,2710.31 1629.89,2710.31 1660,2680.2 v1(1660,2600)
SYNCOUT: J4.5 U2.39 | length 576.7
  Top Layer w9: v1@1410,2580 v1@1413.37,2576.63 ; v1(1416.43,2576.63) v1@1413.37,2576.63 ; U2.39@1421.1,2544.17 1421.1,2568.9 v1@1413.37,2576.63
  Signal Layer 4 w9: J4.5@1260,3045 1260,2895 1416.43,2738.57 v1(1416.43,2576.63)
VBATT: C4.2 C5.1 D1.1 D2.2 J1.1 Q2.2 R10.1 R13.1 TP1.1 | length 20.4
  Bottom Layer w10: R13.1@3914.24,2162.47 3915.23,2162.47 R13.1@3928.93,2148.77
  other v3: 3955.75,2141.69 3955.75,2180.47 4249.52,2452.25 4299.52,2452.25 4249.52,2499.83 4299.52,2499.83 4249.52,2547.42 4299.52,2547.42
VCC: C24.1 C25.1 D9.2 D10.2 J4.3 R44.2 R45.2 U2.15 U2.16 | length 1847.2
  Top Layer w9.5: D10.2@1327.71,2088.77 1351.59,2088.77 1390,2127.18 v1(1390,2148.59) 1413.85,2172.44 C25.1@1445,2172.44 C25.1@1450,2172.44 ; U2.15@1480.16,2315.83 1480.16,2285 1490,2285 1499.84,2285 U2.16@1499.84,2315.83 ; C24.1@1535,2172.44 1535,2146.11 1597.24,2083.87 D9.2@1645.22,2083.87 D9.2@1638.15,2090.93
  Top Layer w24: C25.1@1450,2172.44 C24.1@1535,2172.44 ; 1490,2175 1490,2285
  Signal Layer 4 w10: J4.3@1060,3045 1060,2986.34 1360.75,2685.59 1360.75,2177.84 v1(1390,2148.59)
  Bottom Layer w9.5: v1@1387.5,2152.5 1390,2155 v1(1390,2148.59)
  Bottom Layer w10: R44.2@1085.41,2965 1085.41,2965.98 1060,2991.39 J4.3@1060,3045 1060,3103.61 1085.41,3129.02 R45.2@1085.41,3130
VDDA: C18.2 J4.6 U2.34 U2.36 | length 727.5
  Top Layer w9: C18.2@1460,2652.44 1460,2630 v1(1470,2620) 1479.63,2610.37 1479.63,2578.6 1479.47,2578.44 1479.47,2561.4 1480.16,2560.71 U2.36@1480.16,2544.17 ; U2.34@1519.53,2544.17 1519.53,2559.53 1520.37,2560.37 1520.37,2610.37 v1(1530,2620)
  Signal Layer 4 w9: J4.6@1360,3045 1360,2980 1470,2870 v1(1470,2620)
  Bottom Layer w9: v1(1470,2620) v1(1530,2620)
VIN: C2.1 C3.1 C8.1 C17.2 C20.1 C21.1 C22.1 C23.1 C26.1 C27.1 C28.1 C29.1 C30.1 C31.1 C32.1 C33.1 C34.1 C35.1 J4.12 L1.2 Q5.5 Q6.5 R4.1 R46.2 R47.2 U2.25 | length 3811.7
  Top Layer w9.5: U2.25@1604.17,2420.16 1649.84,2420.16 v1(1650,2420)
  Signal Layer 2 w9.5: J4.12@1960,3045 2110,2895 2340.31,2895 2595.61,2639.7 2595.61,2088.65 2559.32,2052.36
  Signal Layer 2 w16: v3(3668.71,1940.33) 3668.71,1723.75 3610.33,1665.38 3610.33,1095.3 v3(3758.23,947.4)
  Bottom Layer w9.5: R46.2@960,3178.23 960,3210 975,3225 1916.3,3225 1961.3,3180 R47.2@1961.3,3145 ; C17.2@1609.53,2420 v1(1650,2420)
  Bottom Layer w10: J4.12@1960,3045 1960,3143.7 R47.2@1961.3,3145 ; R4.1@3668.28,1987.83 3668.71,1987.4 v3(3668.71,1940.33)
  other v1: 2420,1670 2498.01,1670 560,1680 640,1696.32 2458.01,1710 2538.01,1710 520,1720 600,1720 2420,1750 2498.01,1750 560,1760 640,1760 2458.01,1790 2538.01,1790 520,1800 600,1800 2420,1830 2498.01,1830 560,1840 640,1840 2458.01,1870 2538.01,1870 520,1880 600,1880 2388.56,1890 2300,2140 2380,2140 2460,2140 560,2150 640,2150 720,2150 2260,2180 2340,2180 2420,2180 2500,2180 520,2190 600,2190 680,2190 760,2190 2220,2220 2300,2220 2380,2220 2460,2220 560,2230 640,2230 720,2230 800,2230 2260,2260 2340,2260 2420,2260 2500,2260 520,2270 600,2270 680,2270 760,2270 2300,2300 2380,2300 2460,2300 560,2310 640,2310 720,2310 2340,2340 2420,2340 2500,2340 520,2350 600,2350 680,2350
  other v2: 3429.31,480 3470,480 3660.47,480 3700,480 3883.02,480 3923.71,480 4114.19,480 4153.71,480 3429.31,520.79 3470,520.79 3660.47,520.79 3700,520.79 3883.02,520.79 3923.71,520.79 4114.19,520.79 4153.71,520.79 3429.31,558.19 3470,558.19 3660.47,558.19 3700,558.19 3883.02,558.19 3923.71,558.19 4114.19,558.19 4153.71,558.19 3429.31,594.93 3470,594.93 3660.47,594.93 3700,594.93 3883.02,594.93 3923.71,594.93 4114.19,594.93 4153.71,594.93 3470,635.66 3660.47,635.66 3923.71,635.66 4114.19,635.66 3470,673.06 3509.04,673.06 3545.77,673.06 3584.81,673.06 3621.43,673.06 3660.47,673.06 3923.71,673.06 3962.76,673.06 3999.48,673.06 4038.52,673.06 4075.15,673.06 4114.19,673.06 3470,709.8 3509.04,709.8 3545.77,709.8 3584.81,709.8 3621.43,709.8 3660.47,709.8 3923.71,709.8 3962.76,709.8 3999.48,709.8 4038.52,709.8 4075.15,709.8 4114.19,709.8 4126.16,733.78 4163.56,733.78 4199.63,733.78 4237.04,733.78 4272.96,733.78 4310.37,733.78 4347.1,733.78 4384.51,733.78 3314.5,762.53 3353.54,762.53 3390.27,762.53 3429.31,762.53 3465.93,762.53 3504.97,762.53 4126.16,770.4 4163.56,770.4 4199.63,770.4 4237.04,770.4 4272.96,770.4 4310.37,770.4 4347.1,770.4 4384.51,770.4 3314.5,799.93 3353.54,799.93 3390.27,799.93 3429.31,799.93 3465.93,799.93 3504.97,799.93 4126.16,809.44 4163.56,809.44 4199.63,809.44 4237.04,809.44 4272.96,809.44 4310.37,809.44 4347.1,809.44 4384.51,809.44 3314.5,836.67 3353.54,836.67 3390.27,836.67 3429.31,836.67 3465.93,836.67 3504.97,836.67 3314.5,874.07 3353.54,874.07 3390.27,874.07 3429.31,874.07 3465.93,874.07 3504.97,874.07 3314.5,910 3353.54,910 3390.27,910 3429.31,910 3465.93,910 3504.97,910 3314.5,947.4 3353.54,947.4 3390.27,947.4 3429.31,947.4 3465.93,947.4 3504.97,947.4 3314.5,983.48 3353.54,983.48 3390.27,983.48 3429.31,983.48 3465.93,983.48 3504.97,983.48 3314.5,1020.88 3353.54,1020.88 3390.27,1020.88 3429.31,1020.88 3465.93,1020.88 3504.97,1020.88
VOUT: C38.1 C39.1 C40.1 C41.1 C42.1 C43.1 C46.1 C47.1 C48.1 C49.1 C50.1 C51.1 C52.2 C53.1 C56.1 C57.1 C58.1 C59.1 C60.1 C61.1 C62.1 C63.1 C64.1 C65.1 J3.1 L2.2 L3.2 R33.1 R34.2 R37.2 R40.2 R41.2 TP4.1 | length 2685.1
  Top Layer w9: R41.2@1807.56,2440 1807.56,2440.98 1818.81,2452.23 R41.2@1819.79,2452.23
  Top Layer w10: R40.2@1021.61,2458.58 1021.61,2421.69 1036.13,2407.17 v1(1036.13,2403.93) 1039.33,2403.93 v1@1040.82,2402.44 ; R41.2@1807.56,2440 1811.68,2435.88 R37.2@1861.65,2435.88 1860,2434.23 v1(1860,2403.2) ; 2160.55,1215.91 2160.55,1299.5 2161.05,1300
  Signal Layer 4 w10: v1@870,1420 870,1493.65 861.91,1501.73 861.91,1572.13 1088.06,1798.27 1088.06,2236.67 1042.13,2282.6 1042.13,2372.65 1036.85,2377.93 1036.85,2403.2 v1(1036.13,2403.93) ; v1(1860,2403.2) 1860,2240 1980,2120 1980,1750 2160,1570 v1@2160,1420
  Bottom Layer w10: C53.1@860,1458.5 C53.1@861.91,1456.59
  Bottom Layer w16: C53.1@861.91,1456.59 868.85,1449.65 868.85,1421.15 v1@870,1420 ; v1@2160,1420 C52.2@2160,1464.89
  Bottom Layer w20: C53.1@860,1458.5 R34.2@930,1458.5 ; R33.1@2099.64,1464.89 C52.2@2160,1464.89
  other v1: 677.7,1370 727.7,1370 777.7,1370 827.7,1370 877.7,1370 927.7,1370 977.7,1370 1027.7,1370 2001.5,1371.81 2051.5,1371.81 2101.5,1371.81 2151.5,1371.81 2201.5,1371.81 2251.5,1371.81 2301.5,1371.81 2351.5,1371.81 677.7,1420 727.7,1420 777.7,1420 827.7,1420 877.7,1420 927.7,1420 977.7,1420 1027.7,1420 2001.5,1421.81 2051.5,1421.81 2101.5,1421.81 2151.5,1421.81 2201.5,1421.81 2251.5,1421.81 2301.5,1421.81 2351.5,1421.81
VPWM: J4.11 R42.2 | length 132.9
  Top Layer w24: R42.2@1860,2912.07 J4.11@1860,3045
VREG: C10.1 D8.1 Q4.2 R15.1 R19.1 | length 994
  Top Layer w10: D8.1@3447.56,2497.42 3465.65,2515.52 v3(3531.71,2515.52) ; R19.1@3767.9,2046.2 v3(3767.9,2087.61)
  Signal Layer 2 w12: v3(3531.71,2515.52) 3531.71,2453 3767.9,2216.81 v3(3767.9,2087.61)
  Bottom Layer w10: v3(3531.71,2515.52) 3531.71,2592.6 3600.83,2661.72 C10.1@3614.71,2661.72
  Bottom Layer w12: C10.1@3614.71,2661.72 3639.71,2686.72 Q4.2@3709.46,2686.72 ; R15.1@3767.9,2046.2 v3(3767.9,2087.61)
pads on no net: J3. U1.3 U1.8 U1.17 U1.21 U1.25
copper on no net:
  other v5: 3931.71,1862.82 3900.21,1894.32 3931.71,1894.32 3963.2,1894.32 3931.71,1925.81

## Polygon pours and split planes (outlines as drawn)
PGND on Top Layer "TOP_LAYER_PGND_P1417" (solid, pour order 1417): 0,3500 5250,3500 5250,0 0,0
AGND on Top Layer "TOP_LAYER_AGND_P1374" (solid, remove dead copper, pour order 1374): 1800,2475.53 1920,2475.53 1920,2695.53 1770,2845.53 1311.51,2845.53 1185.07,2719.09 1185.07,2460 1290,2460 1290,2667.35 1318.18,2695.53 1710,2695.53 1800,2605.53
